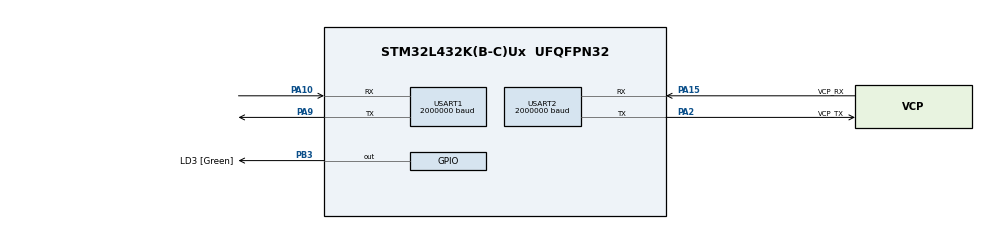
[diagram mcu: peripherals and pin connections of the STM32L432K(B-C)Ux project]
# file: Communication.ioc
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Mcu.Family=STM32L4
Mcu.Name=STM32L432K(B-C)Ux
Mcu.Package=UFQFPN32
NVIC.PriorityGroup=NVIC_PRIORITYGROUP_4
NVIC.USART1_IRQn=true\:0\:0\:false\:false\:true
NVIC.USART2_IRQn=true\:0\:0\:false\:false\:true
PA0.GPIO_Label=MCO [High speed clock in]
PA0.Signal=RCC_CK_IN
PA10.Mode=Asynchronous
PA10.Signal=USART1_RX
PA13\ (JTMS-SWDIO).GPIO_Label=SWDIO
PA13\ (JTMS-SWDIO).Signal=SYS_JTMS-SWDIO
PA14\ (JTCK-SWCLK).GPIO_Label=SWCLK
PA14\ (JTCK-SWCLK).Signal=SYS_JTCK-SWCLK
PA15\ (JTDI).GPIO_Label=VCP_RX
PA15\ (JTDI).Mode=Asynchronous
PA15\ (JTDI).Signal=USART2_RX
PA2.GPIO_Label=VCP_TX
PA2.Mode=Asynchronous
PA2.Signal=USART2_TX
PA9.Mode=Asynchronous
PA9.Signal=USART1_TX
PB3\ (JTDO-TRACESWO).GPIO_Label=LD3 [Green]
PB3\ (JTDO-TRACESWO).Signal=GPIO_Output
PC14-OSC32_IN\ (PC14).Signal=RCC_OSC32_IN
PC15-OSC32_OUT\ (PC15).Signal=RCC_OSC32_OUT
ProjectManager.HeapSize=0x200
ProjectManager.StackSize=0x400
ProjectManager.TargetToolchain=SW4STM32
RCC.AHBFreq_Value=32000000
RCC.APB1Freq_Value=32000000
RCC.APB1TimFreq_Value=32000000
RCC.APB2Freq_Value=32000000
RCC.APB2TimFreq_Value=32000000
RCC.CortexFreq_Value=32000000
RCC.HCLKFreq_Value=32000000
RCC.HSE_VALUE=8000000
RCC.HSI16_VALUE=16000000
RCC.HSI48_VALUE=48000000
RCC.HSI_VALUE=16000000
RCC.LSE_VALUE=32768
RCC.MSI_VALUE=4000000
RCC.PLLMUL=RCC_PLLMUL_4
RCC.PLLN=16
RCC.SYSCLKFreq_VALUE=32000000
RCC.SYSCLKSource=RCC_SYSCLKSOURCE_PLLCLK
RCC.VCOOutputFreq_Value=64000000
USART1.BaudRate=2000000
USART1.VirtualMode-Asynchronous=VM_ASYNC
USART1.WordLength=WORDLENGTH_8B
USART2.BaudRate=2000000
USART2.VirtualMode-Asynchronous=VM_ASYNC
USART2.WordLength=WORDLENGTH_8B
board=NUCLEO-L432KC

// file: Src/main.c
/**
  ******************************************************************************
  * File Name          : main.c
  * Description        : Main program body
  ******************************************************************************
  ** This notice applies to any and all portions of this file
  * that are not between comment pairs USER CODE BEGIN and
  * USER CODE END. Other portions of this file, whether
  * inserted by the user or by software development tools
  * are owned by their respective copyright owners.
  *
  * COPYRIGHT(c) 2018 STMicroelectronics
  *
  * Redistribution and use in source and binary forms, with or without modification,
  * are permitted provided that the following conditions are met:
  *   1. Redistributions of source code must retain the above copyright notice,
  *      this list of conditions and the following disclaimer.
  *   2. Redistributions in binary form must reproduce the above copyright notice,
  *      this list of conditions and the following disclaimer in the documentation
  *      and/or other materials provided with the distribution.
  *   3. Neither the name of STMicroelectronics nor the names of its contributors
  *      may be used to endorse or promote products derived from this software
  *      without specific prior written permission.
  *
  * THIS SOFTWARE IS PROVIDED BY THE COPYRIGHT HOLDERS AND CONTRIBUTORS "AS IS"
  * AND ANY EXPRESS OR IMPLIED WARRANTIES, INCLUDING, BUT NOT LIMITED TO, THE
  * IMPLIED WARRANTIES OF MERCHANTABILITY AND FITNESS FOR A PARTICULAR PURPOSE ARE
  * DISCLAIMED. IN NO EVENT SHALL THE COPYRIGHT HOLDER OR CONTRIBUTORS BE LIABLE
  * FOR ANY DIRECT, INDIRECT, INCIDENTAL, SPECIAL, EXEMPLARY, OR CONSEQUENTIAL
  * DAMAGES (INCLUDING, BUT NOT LIMITED TO, PROCUREMENT OF SUBSTITUTE GOODS OR
  * SERVICES; LOSS OF USE, DATA, OR PROFITS; OR BUSINESS INTERRUPTION) HOWEVER
  * CAUSED AND ON ANY THEORY OF LIABILITY, WHETHER IN CONTRACT, STRICT LIABILITY,
  * OR TORT (INCLUDING NEGLIGENCE OR OTHERWISE) ARISING IN ANY WAY OUT OF THE USE
  * OF THIS SOFTWARE, EVEN IF ADVISED OF THE POSSIBILITY OF SUCH DAMAGE.
  *
  ******************************************************************************
  */
#include "main.h"
#include "stm32l4xx_hal.h"

/* USER CODE BEGIN Includes */
#include <robotGoal.h>
#include <robotState.h>
#include <stdint.h>
#include "serial.h"
#include "string.h"
/* USER CODE END Includes */

UART_HandleTypeDef huart1;
UART_HandleTypeDef huart2;

/* USER CODE BEGIN PV */
/* Private variables ---------------------------------------------------------*/
volatile uint8_t ledState;

RobotGoal robotGoal, *robotGoalPtr;
unsigned char robotGoalData[sizeof(RobotGoal)];
unsigned char *robotGoalDataPtr;

unsigned char buf[10];

unsigned startSeqCount;
unsigned totalBytesRead;

RobotState robotState, *robotStatePtr;

/* USER CODE END PV */

void SystemClock_Config(void);
static void MX_GPIO_Init(void);
static void MX_USART2_UART_Init(void);
static void MX_USART1_UART_Init(void);

/* USER CODE BEGIN PFP */
/* Private function prototypes -----------------------------------------------*/

/* USER CODE END PFP */

int main(void)
{

  /* MCU Configuration----------------------------------------------------------*/

  /* Reset of all peripherals, Initializes the Flash interface and the Systick. */
  HAL_Init();

  /* Configure the system clock */
  SystemClock_Config();

  /* Initialize all configured peripherals */
  MX_GPIO_Init();
  MX_USART2_UART_Init();
  MX_USART1_UART_Init();

  /* USER CODE BEGIN 2 */

	// Blink the LED
	ledState = 0;

	// Receiving
	robotGoal.id = 0;
	robotGoalPtr = &robotGoal;
	robotGoalDataPtr = robotGoalData;
	startSeqCount = 0;
	totalBytesRead = 0;

	// Sending
	robotState.id = 0;
	robotStatePtr = &robotState;
	robotState.start_seq = UINT32_MAX;
	robotState.end_seq = 0;

	HAL_UART_Receive_IT(&huart2, (unsigned char *) &buf, sizeof(buf));

  /* USER CODE END 2 */

  /* Infinite loop */
	while (1) {

  /* USER CODE BEGIN 3 */

		ledState = !ledState;
		HAL_GPIO_WritePin(LD3_GPIO_Port, LD3_Pin, ledState);

		robotState.id++;
		for(int i = 0; i < 80; ++i) {
			robotState.msg[i] = i;
		}

//		send_state(robotStatePtr);
		HAL_Delay(10);
	}
  /* USER CODE END 3 */

}

/** System Clock Configuration
*/
void SystemClock_Config(void)
{

  RCC_OscInitTypeDef RCC_OscInitStruct;
  RCC_ClkInitTypeDef RCC_ClkInitStruct;
  RCC_PeriphCLKInitTypeDef PeriphClkInit;

    /**Initializes the CPU, AHB and APB busses clocks
    */
  RCC_OscInitStruct.OscillatorType = RCC_OSCILLATORTYPE_HSI;
  RCC_OscInitStruct.HSIState = RCC_HSI_ON;
  RCC_OscInitStruct.HSICalibrationValue = 16;
  RCC_OscInitStruct.PLL.PLLState = RCC_PLL_ON;
  RCC_OscInitStruct.PLL.PLLSource = RCC_PLLSOURCE_HSI;
  RCC_OscInitStruct.PLL.PLLM = 1;
  RCC_OscInitStruct.PLL.PLLN = 16;
  RCC_OscInitStruct.PLL.PLLP = RCC_PLLP_DIV7;
  RCC_OscInitStruct.PLL.PLLQ = RCC_PLLQ_DIV2;
  RCC_OscInitStruct.PLL.PLLR = RCC_PLLR_DIV4;
  if (HAL_RCC_OscConfig(&RCC_OscInitStruct) != HAL_OK)
  {
    _Error_Handler(__FILE__, __LINE__);
  }

    /**Initializes the CPU, AHB and APB busses clocks
    */
  RCC_ClkInitStruct.ClockType = RCC_CLOCKTYPE_HCLK|RCC_CLOCKTYPE_SYSCLK
                              |RCC_CLOCKTYPE_PCLK1|RCC_CLOCKTYPE_PCLK2;
  RCC_ClkInitStruct.SYSCLKSource = RCC_SYSCLKSOURCE_PLLCLK;
  RCC_ClkInitStruct.AHBCLKDivider = RCC_SYSCLK_DIV1;
  RCC_ClkInitStruct.APB1CLKDivider = RCC_HCLK_DIV1;
  RCC_ClkInitStruct.APB2CLKDivider = RCC_HCLK_DIV1;

  if (HAL_RCC_ClockConfig(&RCC_ClkInitStruct, FLASH_LATENCY_3) != HAL_OK)
  {
    _Error_Handler(__FILE__, __LINE__);
  }

  PeriphClkInit.PeriphClockSelection = RCC_PERIPHCLK_USART1|RCC_PERIPHCLK_USART2;
  PeriphClkInit.Usart1ClockSelection = RCC_USART1CLKSOURCE_PCLK2;
  PeriphClkInit.Usart2ClockSelection = RCC_USART2CLKSOURCE_PCLK1;
  if (HAL_RCCEx_PeriphCLKConfig(&PeriphClkInit) != HAL_OK)
  {
    _Error_Handler(__FILE__, __LINE__);
  }

    /**Configure the main internal regulator output voltage
    */
  if (HAL_PWREx_ControlVoltageScaling(PWR_REGULATOR_VOLTAGE_SCALE1) != HAL_OK)
  {
    _Error_Handler(__FILE__, __LINE__);
  }

    /**Configure the Systick interrupt time
    */
  HAL_SYSTICK_Config(HAL_RCC_GetHCLKFreq()/1000);

    /**Configure the Systick
    */
  HAL_SYSTICK_CLKSourceConfig(SYSTICK_CLKSOURCE_HCLK);

  /* SysTick_IRQn interrupt configuration */
  HAL_NVIC_SetPriority(SysTick_IRQn, 1, 0);
}

/* USART1 init function */
static void MX_USART1_UART_Init(void)
{

  huart1.Instance = USART1;
  huart1.Init.BaudRate = 1000000;
  huart1.Init.WordLength = UART_WORDLENGTH_8B;
  huart1.Init.StopBits = UART_STOPBITS_1;
  huart1.Init.Parity = UART_PARITY_NONE;
  huart1.Init.Mode = UART_MODE_TX_RX;
  huart1.Init.HwFlowCtl = UART_HWCONTROL_NONE;
  huart1.Init.OverSampling = UART_OVERSAMPLING_16;
  huart1.Init.OneBitSampling = UART_ONE_BIT_SAMPLE_DISABLE;
  huart1.AdvancedInit.AdvFeatureInit = UART_ADVFEATURE_NO_INIT;
  if (HAL_UART_Init(&huart1) != HAL_OK)
  {
    _Error_Handler(__FILE__, __LINE__);
  }

}

/* USART2 init function */
static void MX_USART2_UART_Init(void)
{

  huart2.Instance = USART2;
  huart2.Init.BaudRate = 1000000;
  huart2.Init.WordLength = UART_WORDLENGTH_8B;
  huart2.Init.StopBits = UART_STOPBITS_1;
  huart2.Init.Parity = UART_PARITY_NONE;
  huart2.Init.Mode = UART_MODE_TX_RX;
  huart2.Init.HwFlowCtl = UART_HWCONTROL_NONE;
  huart2.Init.OverSampling = UART_OVERSAMPLING_16;
  huart2.Init.OneBitSampling = UART_ONE_BIT_SAMPLE_DISABLE;
  huart2.AdvancedInit.AdvFeatureInit = UART_ADVFEATURE_NO_INIT;
  if (HAL_UART_Init(&huart2) != HAL_OK)
  {
    _Error_Handler(__FILE__, __LINE__);
  }

}

/** Configure pins as
        * Analog
        * Input
        * Output
        * EVENT_OUT
        * EXTI
*/
static void MX_GPIO_Init(void)
{

  GPIO_InitTypeDef GPIO_InitStruct;

  /* GPIO Ports Clock Enable */
  __HAL_RCC_GPIOC_CLK_ENABLE();
  __HAL_RCC_GPIOA_CLK_ENABLE();
  __HAL_RCC_GPIOB_CLK_ENABLE();

  /*Configure GPIO pin Output Level */
  HAL_GPIO_WritePin(LD3_GPIO_Port, LD3_Pin, GPIO_PIN_RESET);

  /*Configure GPIO pin : LD3_Pin */
  GPIO_InitStruct.Pin = LD3_Pin;
  GPIO_InitStruct.Mode = GPIO_MODE_OUTPUT_PP;
  GPIO_InitStruct.Pull = GPIO_NOPULL;
  GPIO_InitStruct.Speed = GPIO_SPEED_FREQ_LOW;
  HAL_GPIO_Init(LD3_GPIO_Port, &GPIO_InitStruct);

}

/* USER CODE BEGIN 4 */
void HAL_UART_RxCpltCallback(UART_HandleTypeDef * huart) {
	if (huart == &huart2) {

		for(int i = 0; i < sizeof(buf); ++i) {
			if(startSeqCount == 4) {
				*robotGoalDataPtr = buf[i];
				robotGoalDataPtr++;
				totalBytesRead++;

				if(totalBytesRead == sizeof(RobotGoal)) {

					// Process RobotGoal here
					memcpy(&robotGoal, &robotGoalData, sizeof(RobotGoal));
					robotState.id = robotGoal.id;
					for(int i = 0; i < 80; ++i) {
						robotState.msg[i] = robotGoal.msg[i];
					}

					send_state(&robotState);

					robotGoalDataPtr = robotGoalData;
					startSeqCount = 0;
					totalBytesRead = 0;
					continue;
				}
			}
			else {
				if(buf[i] == 255)
					startSeqCount++;
				else
					startSeqCount = 0;
			}
		}

		HAL_UART_AbortReceive_IT(&huart2);
		HAL_UART_Receive_IT(&huart2, (unsigned char *) &buf, sizeof(buf));
	}
}
/* USER CODE END 4 */

void _Error_Handler(char * file, int line)
{
	while (1) {
	}
}

/************************ (C) COPYRIGHT STMicroelectronics *****END OF FILE****/
